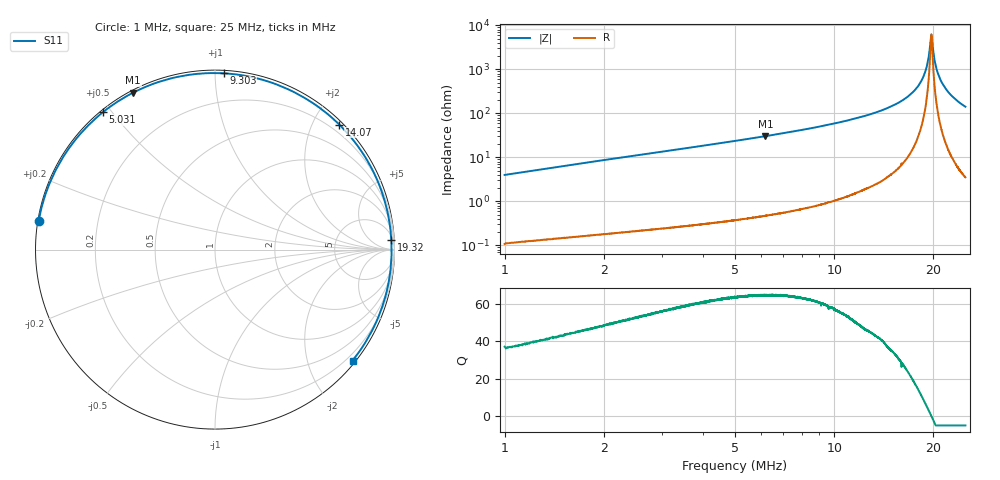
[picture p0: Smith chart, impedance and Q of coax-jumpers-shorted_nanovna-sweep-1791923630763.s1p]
! NanoVNA Web complex sweep
! Processing: unaveraged complex samples; linear segment spacing; no smoothing
# Hz S RI R 50
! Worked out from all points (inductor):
!   5050 points, 1 MHz to 25 MHz, reference 50 ohm
!   read as one part to ground: L = 674 nH near 1.119 MHz
!   highest Q = 64.7 at 6.181 MHz (marker M1), where L = 781 nH
!   self-resonance near 19.71 MHz
!   S11 on the Smith chart (normalised r, x): 1 MHz: 0.00, +0.08; 5.031 MHz: 0.01, +0.48; 9.303 MHz: 0.02, +1.05; 14.07 MHz: 0.06, +2.41; 19.32 MHz: 11, +35; 25 MHz: 0.07, -2.83
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1000000  -0.9831 0.1578
1698691  -0.9528 0.2823
2454418  -0.9033 0.4103
3210145  -0.8375 0.5292
4003896  -0.7527 0.642
5030544  -0.6226 0.7669
6180770  -0.4559 0.8747
7003039  -0.3275 0.9295
8153265  -0.1407 0.9742
9303491  0.0474 0.9822
1.000218e7  0.1589 0.97
1.071038e7  0.2662 0.9456
1.143759e7  0.3713 0.909
1.219332e7  0.4737 0.8597
1.300132e7  0.5746 0.7962
1.407075e7  0.6933 0.6959
1.506413e7  0.786 0.5897
1.600047e7  0.8566 0.4792
1.673243e7  0.9026 0.3899
1.747865e7  0.9381 0.2952
1.824864e7  0.9641 0.1948
1.899961e7  0.9792 0.0946
1.932282e7  0.9825 0.0514
2.064415e7  0.9767 -0.1224
2.199875e7  0.9402 -0.2925
2.339138e7  0.8736 -0.4541
2.437525e7  0.8113 -0.5578
2.49979e7  0.7661 -0.6183
